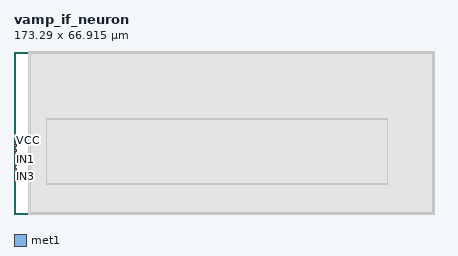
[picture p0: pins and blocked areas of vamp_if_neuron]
MACRO vamp_if_neuron
  CLASS BLOCK ;
  FOREIGN vamp_if_neuron ;
  ORIGIN -55.880 -27.415 ;
  SIZE 173.290 BY 66.915 ;
  PIN VCC
    PORT
      LAYER met1 ;
        RECT 55.880 57.220 56.880 58.220 ;
    END
  END VCC
  PIN V_MEM_BUF
    PORT
      LAYER met1 ;
        RECT 55.880 55.220 56.880 56.220 ;
    END
  END V_MEM_BUF
  PIN VSS
    PORT
      LAYER met1 ;
        RECT 55.880 53.220 56.880 54.220 ;
    END
  END VSS
  PIN rst_n
    PORT
      LAYER met1 ;
        RECT 55.880 51.220 56.880 52.220 ;
    END
  END rst_n
  PIN IN1
    PORT
      LAYER met1 ;
        RECT 55.880 49.220 56.880 50.220 ;
    END
  END IN1
  PIN IN2
    PORT
      LAYER met1 ;
        RECT 55.880 47.220 56.880 48.220 ;
    END
  END IN2
  PIN IN3
    PORT
      LAYER met1 ;
        RECT 55.880 45.220 56.880 46.220 ;
    END
  END IN3
  PIN IN4
    PORT
      LAYER met1 ;
        RECT 55.880 43.220 56.880 44.220 ;
    END
  END IN4
  PIN IN5
    PORT
      LAYER met1 ;
        RECT 55.880 41.220 56.880 42.220 ;
    END
  END IN5
  OBS
      LAYER nwell ;
        RECT 61.765 27.415 229.170 94.330 ;
      LAYER li1 ;
        RECT 61.945 27.595 228.990 94.150 ;
      LAYER met1 ;
        RECT 62.645 28.075 228.450 93.670 ;
      LAYER met3 ;
        RECT 69.135 39.645 210.045 66.615 ;
      LAYER met4 ;
        RECT 69.195 40.040 209.985 66.595 ;
  END
END vamp_if_neuron
END LIBRARY

